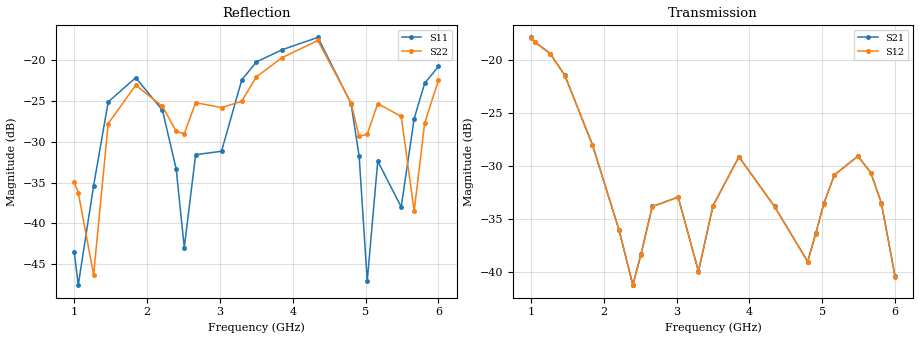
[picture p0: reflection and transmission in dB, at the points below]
!Agilent Technologies,E8364B,MY43040528,A.07.50.67
!Agilent E8364B: A.07.50.67
!Date: Sunday, March 01, 2026 21:32:19
!Correction: S11(Full 2 Port(1,2))
!S21(Full 2 Port(1,2))
!S12(Full 2 Port(1,2))
!S22(Full 2 Port(1,2))
!S2P File: Measurements: S11, S21, S12, S22:
# Hz S  dB  R 50
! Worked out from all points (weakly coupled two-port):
!   451 points, 1 GHz to 6 GHz, reference 50 ohm
!   highest |S21| = -17.89 dB at 1 GHz (marker M1); lowest = -41.2 dB at 2.4 GHz (marker M2)
!   lowest |S11| = -47.6 dB at 1.056 GHz (marker M3), VSWR 1.01, Z = 49.9 + j0.405 ohm
!   |S11| at or under -10 dB: start of sweep to end of sweep
!   |S22| runs from -46.3 to -17.0 dB; largest |S21 - S12| = 0.00044
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1e9  -43.46 54.2  -17.89 26.1  -17.92 26.1  -34.97 15.4
1.055556e9  -47.57 104.4  -18.31 9.6  -18.34 9.6  -36.23 17.1
1.266667e9  -35.36 -166.7  -19.42 -56.4  -19.46 -56.4  -46.31 74.6
1.466667e9  -25.11 164.9  -21.47 -124.6  -21.50 -124.6  -27.77 86.4
1.844444e9  -22.14 93.6  -28.00 114.9  -28.02 115.0  -23.06 -2.5
2.211111e9  -26.13 43.5  -36.05 -6.8  -36.08 -6.8  -25.65 -56.4
2.4e9  -33.33 19.3  -41.22 -129.0  -41.24 -129.1  -28.73 -67.7
2.511111e9  -42.97 69.8  -38.33 144.8  -38.37 144.8  -28.99 -54.7
2.666667e9  -31.58 108.8  -33.82 62.8  -33.85 62.9  -25.20 -58.5
3.022222e9  -31.16 95.6  -32.94 -83.7  -32.97 -83.7  -25.81 -115.7
3.3e9  -22.42 93.7  -39.92 -135.6  -39.96 -135.5  -25.02 -98.1
3.5e9  -20.21 63.1  -33.76 -158.6  -33.78 -158.6  -22.04 -122.5
3.855556e9  -18.71 29.0  -29.14 70.4  -29.17 70.5  -19.68 -154.7
4.344444e9  -17.20 -46.6  -33.82 -110.5  -33.85 -110.5  -17.58 114.2
4.8e9  -25.31 -135.1  -39.02 20.6  -39.05 20.6  -25.24 27.2
4.911111e9  -31.72 -163.5  -36.35 -47.2  -36.39 -47.1  -29.34 26.2
5.022222e9  -47.06 81.1  -33.52 -105.0  -33.56 -105.0  -29.07 44.6
5.166667e9  -32.38 -23.8  -30.85 -172.6  -30.88 -172.5  -25.31 32.3
5.488889e9  -37.99 -33.9  -29.07 46.2  -29.10 46.2  -26.89 -44.5
5.666667e9  -27.15 -8.0  -30.63 -29.4  -30.67 -29.4  -38.49 -14.2
5.811111e9  -22.82 -34.4  -33.51 -87.8  -33.55 -87.8  -27.69 19.0
6e9  -20.76 -70.2  -40.42 -149.9  -40.46 -149.9  -22.47 -13.9
